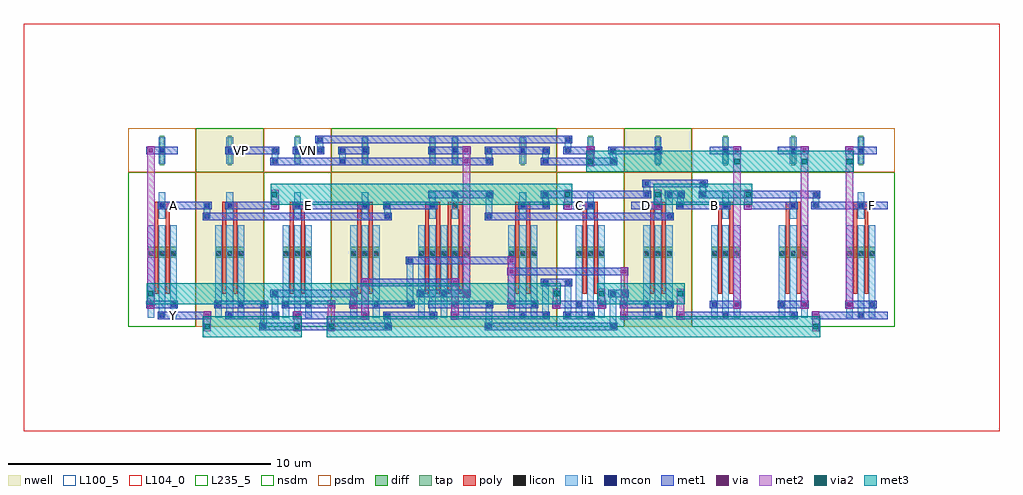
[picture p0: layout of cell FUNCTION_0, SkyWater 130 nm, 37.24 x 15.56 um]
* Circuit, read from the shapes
.subckt FUNCTION_0 A B C D E F VN VP Y
XM1 Y A VN VN sky130_fd_pr__nfet_01v8 w=0.42 l=0.15 m=2
XM2 Y E n1 VN sky130_fd_pr__nfet_01v8 w=0.42 l=0.15 m=2
XM3 Y C VN VN sky130_fd_pr__nfet_01v8 w=0.42 l=0.15 m=2
XM4 VN B VN VN sky130_fd_pr__nfet_01v8 w=0.42 l=0.15 m=2
XM5 VN D VN VN sky130_fd_pr__nfet_01v8 w=0.42 l=0.15 m=2
XM6 n1 F VN VN sky130_fd_pr__nfet_01v8 w=0.42 l=0.15 m=2
XM7 n2 C n3 VP sky130_fd_pr__pfet_01v8 w=0.42 l=0.15 m=2
XM8 Y E n2 VP sky130_fd_pr__pfet_01v8 w=0.42 l=0.15 m=2
XM9 n3 A VP VP sky130_fd_pr__pfet_01v8 w=0.42 l=0.15 m=2
XM10 n4 B VP VP sky130_fd_pr__pfet_01v8 w=0.42 l=0.15 m=2
XM11 Y F n2 VP sky130_fd_pr__pfet_01v8 w=0.42 l=0.15 m=2
XM12 n2 D n4 VP sky130_fd_pr__pfet_01v8 w=0.42 l=0.15 m=2
.ends

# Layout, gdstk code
from math import pi, radians
import gdstk
lib = gdstk.Library(unit=1e-6, precision=1e-09)
def R(c, l, rs):  # rectangles x0, y0, x1, y1
    for r in rs: c.add(gdstk.rectangle(r[:2], r[2:], *l))
def A(c, l, x, y, w, h, nx, ny, dx, dy):  # array of equal rectangles
    R(c, l, [(x+i*dx, y+j*dy, x+i*dx+w, y+j*dy+h) for i in range(nx) for j in range(ny)])
def P(c, l, *ps):  # polygons
    for p in ps: c.add(gdstk.Polygon(p, *l))
nwell = (64, 20)
diff = (65, 20)
tap = (65, 44)
poly = (66, 20)
licon = (66, 44)
li1 = (67, 20)
mcon = (67, 44)
met1 = (68, 20)
via = (68, 44)
met2 = (69, 20)
via2 = (69, 44)
met3 = (70, 20)
nsdm = (93, 44)
psdm = (94, 20)
L100_5 = (100, 5)
L104_0 = (104, 0)
L235_5 = (235, 5)

dp_pmos_89584417_x1_y1_1 = lib.new_cell('DP_PMOS_89584417_X1_Y1_1676811973')
R(dp_pmos_89584417_x1_y1_1, nwell, [(0,0,3.44,7.56)])
R(dp_pmos_89584417_x1_y1_1, diff, [(0.735,2.625,2.705,3.045)])
R(dp_pmos_89584417_x1_y1_1, tap, [(1.205,6.16,1.375,7.28), (2.065,6.16,2.235,7.28)])
A(dp_pmos_89584417_x1_y1_1, poly, 1, 1.26, 0.15, 3.36, 4, 1, 0.43, 0)
R(dp_pmos_89584417_x1_y1_1, poly, [(1,4.485,1.58,4.755), (1.86,4.485,2.44,4.755)])
A(dp_pmos_89584417_x1_y1_1, licon, 0.775, 2.705, 0.17, 0.17, 3, 1, 0.43, 0)
A(dp_pmos_89584417_x1_y1_1, licon, 1.635, 2.705, 0.17, 0.17, 3, 1, 0.43, 0)
R(dp_pmos_89584417_x1_y1_1, licon, [(1.205,4.535,1.375,4.705), (2.065,4.535,2.235,4.705), (1.205,6.635,1.375,6.805), (2.065,6.635,2.235,6.805)])
A(dp_pmos_89584417_x1_y1_1, li1, 0.735, 0.335, 0.25, 3.53, 5, 1, 0.43, 0)
R(dp_pmos_89584417_x1_y1_1, li1, [(1.165,4.115,1.415,5.125), (2.025,4.115,2.275,5.125), (1.165,6.215,1.415,7.225), (2.025,6.215,2.275,7.225)])
A(dp_pmos_89584417_x1_y1_1, mcon, 0.775, 1.175, 0.17, 0.17, 3, 1, 0.86, 0)
R(dp_pmos_89584417_x1_y1_1, mcon, [(1.205,0.335,1.375,0.505), (2.065,0.755,2.235,0.925), (1.205,4.535,1.375,4.705), (2.065,4.955,2.235,5.125), (1.205,6.635,1.375,6.805), (2.065,6.635,2.235,6.805)])
R(dp_pmos_89584417_x1_y1_1, met1, [(0.26,0.28,1.46,0.56), (1.12,0.7,2.32,0.98), (0.69,1.12,2.75,1.4), (0.26,4.48,1.46,4.76), (1.12,4.9,2.32,5.18), (1.12,6.58,2.75,6.86)])
R(dp_pmos_89584417_x1_y1_1, via, [(2.505,1.185,2.655,1.335), (2.505,6.645,2.655,6.795)])
R(dp_pmos_89584417_x1_y1_1, met2, [(2.44,1.1,2.72,6.88)])
R(dp_pmos_89584417_x1_y1_1, nsdm, [(0,5.88,3.44,7.56)])
R(dp_pmos_89584417_x1_y1_1, psdm, [(0,0,3.44,5.88)])
R(dp_pmos_89584417_x1_y1_1, L100_5, [(0,0,3.44,7.56)])

nmos_s_91441724_x1_y1_16 = lib.new_cell('NMOS_S_91441724_X1_Y1_1676811975')
R(nmos_s_91441724_x1_y1_16, diff, [(0.735,2.625,1.845,3.045)])
R(nmos_s_91441724_x1_y1_16, tap, [(1.205,6.16,1.375,7.28)])
R(nmos_s_91441724_x1_y1_16, poly, [(1,1.26,1.15,4.62), (1.43,1.26,1.58,4.62), (1,4.485,1.58,4.755)])
A(nmos_s_91441724_x1_y1_16, licon, 0.775, 2.705, 0.17, 0.17, 3, 1, 0.43, 0)
R(nmos_s_91441724_x1_y1_16, licon, [(1.205,4.535,1.375,4.705), (1.205,6.635,1.375,6.805)])
A(nmos_s_91441724_x1_y1_16, li1, 0.735, 0.335, 0.25, 3.53, 3, 1, 0.43, 0)
R(nmos_s_91441724_x1_y1_16, li1, [(1.165,4.115,1.415,5.125), (1.165,6.215,1.415,7.225)])
R(nmos_s_91441724_x1_y1_16, mcon, [(1.205,0.335,1.375,0.505), (0.775,0.755,0.945,0.925), (1.635,0.755,1.805,0.925), (1.205,4.535,1.375,4.705), (1.205,6.635,1.375,6.805)])
R(nmos_s_91441724_x1_y1_16, met1, [(0.26,0.28,1.46,0.56), (0.69,0.7,1.89,0.98), (0.26,4.48,1.46,4.76), (0.69,6.58,1.89,6.86)])
R(nmos_s_91441724_x1_y1_16, via, [(1.645,0.765,1.795,0.915), (1.645,6.645,1.795,6.795)])
R(nmos_s_91441724_x1_y1_16, met2, [(1.58,0.68,1.86,6.88)])
R(nmos_s_91441724_x1_y1_16, nsdm, [(0,0,2.58,5.88)])
R(nmos_s_91441724_x1_y1_16, psdm, [(0,5.88,2.58,7.56)])
R(nmos_s_91441724_x1_y1_16, L100_5, [(0,0,2.58,7.56)])

nmos_4t_21196599_x1_y1_1 = lib.new_cell('NMOS_4T_21196599_X1_Y1_1676811974')
R(nmos_4t_21196599_x1_y1_1, diff, [(0.735,2.625,1.845,3.045)])
R(nmos_4t_21196599_x1_y1_1, tap, [(1.205,6.16,1.375,7.28)])
R(nmos_4t_21196599_x1_y1_1, poly, [(1,1.26,1.15,4.62), (1.43,1.26,1.58,4.62), (1,4.485,1.58,4.755)])
A(nmos_4t_21196599_x1_y1_1, licon, 0.775, 2.705, 0.17, 0.17, 3, 1, 0.43, 0)
R(nmos_4t_21196599_x1_y1_1, licon, [(1.205,4.535,1.375,4.705), (1.205,6.635,1.375,6.805)])
A(nmos_4t_21196599_x1_y1_1, li1, 0.735, 0.335, 0.25, 3.53, 3, 1, 0.43, 0)
R(nmos_4t_21196599_x1_y1_1, li1, [(1.165,4.115,1.415,5.125), (1.165,6.215,1.415,7.225)])
R(nmos_4t_21196599_x1_y1_1, mcon, [(1.205,0.335,1.375,0.505), (0.775,0.755,0.945,0.925), (1.635,0.755,1.805,0.925), (1.205,4.535,1.375,4.705), (1.205,6.635,1.375,6.805)])
R(nmos_4t_21196599_x1_y1_1, met1, [(0.26,0.28,1.46,0.56), (0.69,0.7,1.89,0.98), (0.26,4.48,1.46,4.76), (0.26,6.58,1.46,6.86)])
R(nmos_4t_21196599_x1_y1_1, nsdm, [(0,0,2.58,5.88)])
R(nmos_4t_21196599_x1_y1_1, psdm, [(0,5.88,2.58,7.56)])
R(nmos_4t_21196599_x1_y1_1, L100_5, [(0,0,2.58,7.56)])

pmos_4t_77116389_x1_y1_1 = lib.new_cell('PMOS_4T_77116389_X1_Y1_1676811976')
R(pmos_4t_77116389_x1_y1_1, nwell, [(0,0,2.58,7.56)])
R(pmos_4t_77116389_x1_y1_1, diff, [(0.735,2.625,1.845,3.045)])
R(pmos_4t_77116389_x1_y1_1, tap, [(1.205,6.16,1.375,7.28)])
R(pmos_4t_77116389_x1_y1_1, poly, [(1,1.26,1.15,4.62), (1.43,1.26,1.58,4.62), (1,4.485,1.58,4.755)])
A(pmos_4t_77116389_x1_y1_1, licon, 0.775, 2.705, 0.17, 0.17, 3, 1, 0.43, 0)
R(pmos_4t_77116389_x1_y1_1, licon, [(1.205,4.535,1.375,4.705), (1.205,6.635,1.375,6.805)])
A(pmos_4t_77116389_x1_y1_1, li1, 0.735, 0.335, 0.25, 3.53, 3, 1, 0.43, 0)
R(pmos_4t_77116389_x1_y1_1, li1, [(1.165,4.115,1.415,5.125), (1.165,6.215,1.415,7.225)])
R(pmos_4t_77116389_x1_y1_1, mcon, [(1.205,0.335,1.375,0.505), (0.775,0.755,0.945,0.925), (1.635,0.755,1.805,0.925), (1.205,4.535,1.375,4.705), (1.205,6.635,1.375,6.805)])
R(pmos_4t_77116389_x1_y1_1, met1, [(0.26,0.28,1.46,0.56), (0.69,0.7,1.89,0.98), (0.26,4.48,1.46,4.76), (0.26,6.58,1.46,6.86)])
R(pmos_4t_77116389_x1_y1_1, nsdm, [(0,5.88,2.58,7.56)])
R(pmos_4t_77116389_x1_y1_1, psdm, [(0,0,2.58,5.88)])
R(pmos_4t_77116389_x1_y1_1, L100_5, [(0,0,2.58,7.56)])

function_0 = lib.new_cell('FUNCTION_0')
A(function_0, li1, 15.785, 4.62, 0.25, 0.42, 3, 1, 5.16, 0)
R(function_0, li1, [(5.035,-0.085,5.285,0.085), (5.035,-0.085,5.285,0.085), (9.765,-0.085,10.015,0.085), (9.765,-0.085,10.015,0.085), (13.635,-0.085,13.885,0.085), (13.635,-0.085,13.885,0.085), (18.365,-0.085,18.615,0.085), (18.365,-0.085,18.615,0.085), (5.035,0,5.285,0.84), (9.765,0,10.015,0.42), (13.635,0,13.885,0.84), (18.365,0,18.615,1.26), (5.465,0.335,5.715,0.505), (5.465,0.335,5.715,0.505), (5.465,0.335,5.715,0.505), (5.465,0.335,5.715,0.505), (5.465,0.335,5.715,0.505), (5.465,0.335,5.715,0.505), (9.765,0.335,10.015,0.505), (9.765,0.335,10.015,0.505), (15.785,0.335,16.035,0.505), (15.785,0.335,16.035,0.505), (16.645,0.335,16.895,0.505), (16.645,0.335,16.895,0.505), (5.465,0.42,5.715,1.26), (15.785,0.42,16.035,1.68), (16.645,0.42,16.895,1.68), (5.035,0.755,5.285,0.925), (5.035,0.755,5.285,0.925), (10.625,0.755,10.875,0.925), (10.625,0.755,10.875,0.925), (10.625,0.755,10.875,0.925), (10.625,0.755,10.875,0.925), (13.635,0.755,13.885,0.925), (13.635,0.755,13.885,0.925), (18.795,0.755,19.045,0.925), (18.795,0.755,19.045,0.925), (10.625,0.84,10.875,2.52), (18.795,0.84,19.045,1.26), (5.465,1.175,5.715,1.345), (5.465,1.175,5.715,1.345), (5.465,1.175,5.715,1.345), (5.465,1.175,5.715,1.345), (5.465,1.175,5.715,1.345), (5.465,1.175,5.715,1.345), (18.365,1.175,18.615,1.345), (18.365,1.175,18.615,1.345), (18.795,1.175,19.045,1.345), (18.795,1.175,19.045,1.345), (15.785,1.595,16.035,1.765), (15.785,1.595,16.035,1.765), (16.645,1.595,16.895,1.765), (16.645,1.595,16.895,1.765), (10.625,2.435,10.875,2.605), (10.625,2.435,10.875,2.605), (10.625,2.435,10.875,2.605), (10.625,2.435,10.875,2.605), (2.885,4.115,3.135,4.285), (2.885,4.115,3.135,4.285), (9.765,4.115,10.015,4.285), (9.765,4.115,10.015,4.285), (13.635,4.115,13.885,4.285), (13.635,4.115,13.885,4.285), (20.515,4.115,20.765,4.285), (20.515,4.115,20.765,4.285), (2.885,4.2,3.135,4.62), (9.765,4.2,10.015,4.62), (13.635,4.2,13.885,5.04), (20.515,4.2,20.765,5.04), (2.885,4.535,3.135,4.705), (2.885,4.535,3.135,4.705), (9.765,4.535,10.015,4.705), (9.765,4.535,10.015,4.705), (15.785,4.535,16.035,4.705), (15.785,4.535,16.035,4.705), (20.945,4.535,21.195,4.705), (20.945,4.535,21.195,4.705), (26.105,4.535,26.355,4.705), (26.105,4.535,26.355,4.705), (13.635,4.955,13.885,5.125), (13.635,4.955,13.885,5.125), (15.785,4.955,16.035,5.125), (15.785,4.955,16.035,5.125), (19.655,4.955,19.905,5.125), (19.655,4.955,19.905,5.125), (20.515,4.955,20.765,5.125), (20.515,4.955,20.765,5.125), (20.945,4.955,21.195,5.125), (20.945,4.955,21.195,5.125), (21.805,4.955,22.055,5.125), (21.805,4.955,22.055,5.125), (26.105,4.955,26.355,5.125), (26.105,4.955,26.355,5.125), (19.655,5.04,19.905,5.46), (21.805,5.04,22.055,5.46), (19.655,5.375,19.905,5.545), (19.655,5.375,19.905,5.545), (21.805,5.375,22.055,5.545), (21.805,5.375,22.055,5.545), (5.465,6.215,5.715,6.385), (5.465,6.215,5.715,6.385), (5.465,6.215,5.715,6.385), (5.465,6.215,5.715,6.385), (5.465,6.215,5.715,6.385), (5.465,6.215,5.715,6.385), (5.465,6.215,5.715,6.385), (5.465,6.215,5.715,6.385), (8.045,6.215,8.295,6.385), (8.045,6.215,8.295,6.385), (8.045,6.215,8.295,6.385), (8.045,6.215,8.295,6.385), (8.045,6.215,8.295,6.385), (8.045,6.215,8.295,6.385), (8.045,6.215,8.295,6.385), (8.045,6.215,8.295,6.385), (13.635,6.215,13.885,6.385), (13.635,6.215,13.885,6.385), (13.635,6.215,13.885,6.385), (13.635,6.215,13.885,6.385), (13.635,6.215,13.885,6.385), (13.635,6.215,13.885,6.385), (15.785,6.215,16.035,6.385), (15.785,6.215,16.035,6.385), (15.785,6.215,16.035,6.385), (15.785,6.215,16.035,6.385), (18.365,6.215,18.615,6.385), (18.365,6.215,18.615,6.385), (18.365,6.215,18.615,6.385), (18.365,6.215,18.615,6.385), (5.465,6.3,5.715,6.72), (8.045,6.3,8.295,6.72), (13.635,6.3,13.885,6.72), (15.785,6.3,16.035,6.72), (18.365,6.3,18.615,6.72), (5.465,6.635,5.715,6.805), (5.465,6.635,5.715,6.805), (5.465,6.635,5.715,6.805), (5.465,6.635,5.715,6.805), (5.465,6.635,5.715,6.805), (5.465,6.635,5.715,6.805), (5.465,6.635,5.715,6.805), (5.465,6.635,5.715,6.805), (7.185,6.635,7.435,6.805), (7.185,6.635,7.435,6.805), (7.185,6.635,7.435,6.805), (7.185,6.635,7.435,6.805), (7.185,6.635,7.435,6.805), (7.185,6.635,7.435,6.805), (7.185,6.635,7.435,6.805), (7.185,6.635,7.435,6.805), (8.045,6.635,8.295,6.805), (8.045,6.635,8.295,6.805), (8.045,6.635,8.295,6.805), (8.045,6.635,8.295,6.805), (8.045,6.635,8.295,6.805), (8.045,6.635,8.295,6.805), (8.045,6.635,8.295,6.805), (8.045,6.635,8.295,6.805), (13.635,6.635,13.885,6.805), (13.635,6.635,13.885,6.805), (13.635,6.635,13.885,6.805), (13.635,6.635,13.885,6.805), (13.635,6.635,13.885,6.805), (13.635,6.635,13.885,6.805), (15.785,6.635,16.035,6.805), (15.785,6.635,16.035,6.805), (15.785,6.635,16.035,6.805), (15.785,6.635,16.035,6.805), (16.645,6.635,16.895,6.805), (16.645,6.635,16.895,6.805), (16.645,6.635,16.895,6.805), (16.645,6.635,16.895,6.805), (16.645,6.635,16.895,6.805), (16.645,6.635,16.895,6.805), (16.645,6.635,16.895,6.805), (16.645,6.635,16.895,6.805), (18.365,6.635,18.615,6.805), (18.365,6.635,18.615,6.805), (18.365,6.635,18.615,6.805), (18.365,6.635,18.615,6.805), (7.185,6.72,7.435,7.14), (16.645,6.72,16.895,7.14), (7.185,7.055,7.435,7.225), (7.185,7.055,7.435,7.225), (7.185,7.055,7.435,7.225), (7.185,7.055,7.435,7.225), (7.185,7.055,7.435,7.225), (7.185,7.055,7.435,7.225), (7.185,7.055,7.435,7.225), (7.185,7.055,7.435,7.225), (16.645,7.055,16.895,7.225), (16.645,7.055,16.895,7.225), (16.645,7.055,16.895,7.225), (16.645,7.055,16.895,7.225), (16.645,7.055,16.895,7.225), (16.645,7.055,16.895,7.225), (16.645,7.055,16.895,7.225), (16.645,7.055,16.895,7.225)])
R(function_0, mcon, [(5.075,-0.085,5.245,0.085), (5.075,-0.085,5.245,0.085), (9.805,-0.085,9.975,0.085), (9.805,-0.085,9.975,0.085), (13.675,-0.085,13.845,0.085), (13.675,-0.085,13.845,0.085), (18.405,-0.085,18.575,0.085), (18.405,-0.085,18.575,0.085), (5.505,0.335,5.675,0.505), (5.505,0.335,5.675,0.505), (5.505,0.335,5.675,0.505), (5.505,0.335,5.675,0.505), (5.505,0.335,5.675,0.505), (5.505,0.335,5.675,0.505), (9.805,0.335,9.975,0.505), (9.805,0.335,9.975,0.505), (15.825,0.335,15.995,0.505), (15.825,0.335,15.995,0.505), (16.685,0.335,16.855,0.505), (16.685,0.335,16.855,0.505), (5.075,0.755,5.245,0.925), (5.075,0.755,5.245,0.925), (10.665,0.755,10.835,0.925), (10.665,0.755,10.835,0.925), (10.665,0.755,10.835,0.925), (10.665,0.755,10.835,0.925), (13.675,0.755,13.845,0.925), (13.675,0.755,13.845,0.925), (18.835,0.755,19.005,0.925), (18.835,0.755,19.005,0.925), (5.505,1.175,5.675,1.345), (5.505,1.175,5.675,1.345), (5.505,1.175,5.675,1.345), (5.505,1.175,5.675,1.345), (5.505,1.175,5.675,1.345), (5.505,1.175,5.675,1.345), (18.405,1.175,18.575,1.345), (18.405,1.175,18.575,1.345), (18.835,1.175,19.005,1.345), (18.835,1.175,19.005,1.345), (15.825,1.595,15.995,1.765), (15.825,1.595,15.995,1.765), (16.685,1.595,16.855,1.765), (16.685,1.595,16.855,1.765), (10.665,2.435,10.835,2.605), (10.665,2.435,10.835,2.605), (10.665,2.435,10.835,2.605), (10.665,2.435,10.835,2.605), (2.925,4.115,3.095,4.285), (2.925,4.115,3.095,4.285), (9.805,4.115,9.975,4.285), (9.805,4.115,9.975,4.285), (13.675,4.115,13.845,4.285), (13.675,4.115,13.845,4.285), (20.555,4.115,20.725,4.285), (20.555,4.115,20.725,4.285), (2.925,4.535,3.095,4.705), (2.925,4.535,3.095,4.705), (9.805,4.535,9.975,4.705), (9.805,4.535,9.975,4.705), (15.825,4.535,15.995,4.705), (15.825,4.535,15.995,4.705), (20.985,4.535,21.155,4.705), (20.985,4.535,21.155,4.705), (26.145,4.535,26.315,4.705), (26.145,4.535,26.315,4.705), (13.675,4.955,13.845,5.125), (13.675,4.955,13.845,5.125), (15.825,4.955,15.995,5.125), (15.825,4.955,15.995,5.125), (19.695,4.955,19.865,5.125), (19.695,4.955,19.865,5.125), (20.555,4.955,20.725,5.125), (20.555,4.955,20.725,5.125), (20.985,4.955,21.155,5.125), (20.985,4.955,21.155,5.125), (21.845,4.955,22.015,5.125), (21.845,4.955,22.015,5.125), (26.145,4.955,26.315,5.125), (26.145,4.955,26.315,5.125), (19.695,5.375,19.865,5.545), (19.695,5.375,19.865,5.545), (21.845,5.375,22.015,5.545), (21.845,5.375,22.015,5.545), (5.505,6.215,5.675,6.385), (5.505,6.215,5.675,6.385), (5.505,6.215,5.675,6.385), (5.505,6.215,5.675,6.385), (5.505,6.215,5.675,6.385), (5.505,6.215,5.675,6.385), (5.505,6.215,5.675,6.385), (5.505,6.215,5.675,6.385), (8.085,6.215,8.255,6.385), (8.085,6.215,8.255,6.385), (8.085,6.215,8.255,6.385), (8.085,6.215,8.255,6.385), (8.085,6.215,8.255,6.385), (8.085,6.215,8.255,6.385), (8.085,6.215,8.255,6.385), (8.085,6.215,8.255,6.385), (13.675,6.215,13.845,6.385), (13.675,6.215,13.845,6.385), (13.675,6.215,13.845,6.385), (13.675,6.215,13.845,6.385), (13.675,6.215,13.845,6.385), (13.675,6.215,13.845,6.385), (15.825,6.215,15.995,6.385), (15.825,6.215,15.995,6.385), (15.825,6.215,15.995,6.385), (15.825,6.215,15.995,6.385), (18.405,6.215,18.575,6.385), (18.405,6.215,18.575,6.385), (18.405,6.215,18.575,6.385), (18.405,6.215,18.575,6.385), (5.505,6.635,5.675,6.805), (5.505,6.635,5.675,6.805), (5.505,6.635,5.675,6.805), (5.505,6.635,5.675,6.805), (5.505,6.635,5.675,6.805), (5.505,6.635,5.675,6.805), (5.505,6.635,5.675,6.805), (5.505,6.635,5.675,6.805), (7.225,6.635,7.395,6.805), (7.225,6.635,7.395,6.805), (7.225,6.635,7.395,6.805), (7.225,6.635,7.395,6.805), (7.225,6.635,7.395,6.805), (7.225,6.635,7.395,6.805), (7.225,6.635,7.395,6.805), (7.225,6.635,7.395,6.805), (8.085,6.635,8.255,6.805), (8.085,6.635,8.255,6.805), (8.085,6.635,8.255,6.805), (8.085,6.635,8.255,6.805), (8.085,6.635,8.255,6.805), (8.085,6.635,8.255,6.805), (8.085,6.635,8.255,6.805), (8.085,6.635,8.255,6.805), (13.675,6.635,13.845,6.805), (13.675,6.635,13.845,6.805), (13.675,6.635,13.845,6.805), (13.675,6.635,13.845,6.805), (13.675,6.635,13.845,6.805), (13.675,6.635,13.845,6.805), (15.825,6.635,15.995,6.805), (15.825,6.635,15.995,6.805), (15.825,6.635,15.995,6.805), (15.825,6.635,15.995,6.805), (16.685,6.635,16.855,6.805), (16.685,6.635,16.855,6.805), (16.685,6.635,16.855,6.805), (16.685,6.635,16.855,6.805), (16.685,6.635,16.855,6.805), (16.685,6.635,16.855,6.805), (16.685,6.635,16.855,6.805), (16.685,6.635,16.855,6.805), (18.405,6.635,18.575,6.805), (18.405,6.635,18.575,6.805), (18.405,6.635,18.575,6.805), (18.405,6.635,18.575,6.805), (7.225,7.055,7.395,7.225), (7.225,7.055,7.395,7.225), (7.225,7.055,7.395,7.225), (7.225,7.055,7.395,7.225), (7.225,7.055,7.395,7.225), (7.225,7.055,7.395,7.225), (7.225,7.055,7.395,7.225), (7.225,7.055,7.395,7.225), (16.685,7.055,16.855,7.225), (16.685,7.055,16.855,7.225), (16.685,7.055,16.855,7.225), (16.685,7.055,16.855,7.225), (16.685,7.055,16.855,7.225), (16.685,7.055,16.855,7.225), (16.685,7.055,16.855,7.225), (16.685,7.055,16.855,7.225)])
A(function_0, met1, 2.15, 0.28, 0.86, 0.28, 4, 2, 2.58, 4.2)
R(function_0, met1, [(4.99,-0.14,5.33,0.14), (4.99,-0.14,5.33,0.14), (5.16,-0.14,9.89,0.14), (9.72,-0.14,10.06,0.14), (9.72,-0.14,10.06,0.14), (13.59,-0.14,13.93,0.14), (13.59,-0.14,13.93,0.14), (13.76,-0.14,18.49,0.14), (18.32,-0.14,18.66,0.14), (18.32,-0.14,18.66,0.14), (2.85,0.28,3.17,0.56), (2.85,0.28,3.17,0.56), (2.85,0.28,3.17,0.56), (2.85,0.28,3.17,0.56), (2.85,0.28,3.17,0.56), (2.85,0.28,3.17,0.56), (2.85,0.28,3.17,0.56), (2.85,0.28,3.17,0.56), (5.42,0.28,5.76,0.56), (5.42,0.28,5.76,0.56), (5.42,0.28,5.76,0.56), (5.42,0.28,5.76,0.56), (5.42,0.28,5.76,0.56), (5.42,0.28,5.76,0.56), (6.29,0.28,6.61,0.56), (6.29,0.28,6.61,0.56), (6.29,0.28,6.61,0.56), (6.29,0.28,6.61,0.56), (6.29,0.28,6.61,0.56), (6.29,0.28,6.61,0.56), (6.29,0.28,6.61,0.56), (6.29,0.28,6.61,0.56), (8.87,0.28,9.19,0.56), (8.87,0.28,9.19,0.56), (8.87,0.28,9.19,0.56), (8.87,0.28,9.19,0.56), (9.72,0.28,10.06,0.56), (9.72,0.28,10.06,0.56), (12.31,0.28,12.63,0.56), (12.31,0.28,12.63,0.56), (12.31,0.28,12.63,0.56), (12.31,0.28,12.63,0.56), (12.47,0.28,15.05,0.56), (15.74,0.28,16.08,0.56), (15.74,0.28,16.08,0.56), (16.6,0.28,16.94,0.56), (16.6,0.28,16.94,0.56), (18.76,0.28,19.08,0.56), (18.76,0.28,19.08,0.56), (18.92,0.28,19.35,0.56), (20.91,0.28,21.23,0.56), (20.91,0.28,21.23,0.56), (20.91,0.28,21.23,0.56), (20.91,0.28,21.23,0.56), (21.07,0.28,21.93,0.56), (22.79,0.28,24.51,0.56), (26.07,0.28,26.39,0.56), (26.07,0.28,26.39,0.56), (26.23,0.28,27.95,0.56), (4.3,0.7,5.16,0.98), (4.99,0.7,5.33,0.98), (4.99,0.7,5.33,0.98), (6.88,0.7,7.74,0.98), (7.58,0.7,7.9,0.98), (7.58,0.7,7.9,0.98), (8.44,0.7,8.76,0.98), (8.44,0.7,8.76,0.98), (8.44,0.7,8.76,0.98), (8.44,0.7,8.76,0.98), (8.44,0.7,8.76,0.98), (8.44,0.7,8.76,0.98), (9.46,0.7,10.75,0.98), (10.58,0.7,10.92,0.98), (10.58,0.7,10.92,0.98), (10.58,0.7,10.92,0.98), (10.58,0.7,10.92,0.98), (12.47,0.7,13.76,0.98), (13.59,0.7,13.93,0.98), (13.59,0.7,13.93,0.98), (14.46,0.7,14.78,0.98), (14.46,0.7,14.78,0.98), (14.46,0.7,14.78,0.98), (14.46,0.7,14.78,0.98), (16.18,0.7,16.5,0.98), (16.18,0.7,16.5,0.98), (16.18,0.7,16.5,0.98), (16.18,0.7,16.5,0.98), (16.18,0.7,16.5,0.98), (16.18,0.7,16.5,0.98), (16.34,0.7,17.2,0.98), (17.9,0.7,18.22,0.98), (17.9,0.7,18.22,0.98), (17.9,0.7,18.22,0.98), (17.9,0.7,18.22,0.98), (18.75,0.7,19.09,0.98), (18.75,0.7,19.09,0.98), (18.92,0.7,19.78,0.98), (5.42,1.12,5.76,1.4), (5.42,1.12,5.76,1.4), (5.42,1.12,5.76,1.4), (5.42,1.12,5.76,1.4), (5.42,1.12,5.76,1.4), (5.42,1.12,5.76,1.4), (5.59,1.12,8.6,1.4), (8.44,1.12,8.76,1.4), (8.44,1.12,8.76,1.4), (8.44,1.12,8.76,1.4), (8.44,1.12,8.76,1.4), (8.44,1.12,8.76,1.4), (8.44,1.12,8.76,1.4), (18.32,1.12,18.66,1.4), (18.32,1.12,18.66,1.4), (18.49,1.12,18.92,1.4), (18.75,1.12,19.09,1.4), (18.75,1.12,19.09,1.4), (8.87,1.54,9.19,1.82), (8.87,1.54,9.19,1.82), (8.87,1.54,9.19,1.82), (8.87,1.54,9.19,1.82), (9.03,1.54,12.47,1.82), (12.31,1.54,12.63,1.82), (12.31,1.54,12.63,1.82), (12.31,1.54,12.63,1.82), (12.31,1.54,12.63,1.82), (15.74,1.54,16.08,1.82), (15.74,1.54,16.08,1.82), (15.91,1.54,16.77,1.82), (16.6,1.54,16.94,1.82), (16.6,1.54,16.94,1.82), (14.46,1.96,14.78,2.24), (14.46,1.96,14.78,2.24), (14.62,1.96,18.92,2.24), (18.76,1.96,19.08,2.24), (18.76,1.96,19.08,2.24), (10.58,2.38,10.92,2.66), (10.58,2.38,10.92,2.66), (10.58,2.38,10.92,2.66), (10.58,2.38,10.92,2.66), (10.75,2.38,14.62,2.66), (14.46,2.38,14.78,2.66), (14.46,2.38,14.78,2.66), (14.46,2.38,14.78,2.66), (14.46,2.38,14.78,2.66), (2.84,4.06,3.18,4.34), (2.84,4.06,3.18,4.34), (3.01,4.06,9.89,4.34), (9.72,4.06,10.06,4.34), (9.72,4.06,10.06,4.34), (13.59,4.06,13.93,4.34), (13.59,4.06,13.93,4.34), (13.76,4.06,20.64,4.34), (20.47,4.06,20.81,4.34), (20.47,4.06,20.81,4.34), (2.84,4.48,3.18,4.76), (2.84,4.48,3.18,4.76), (5.43,4.48,5.75,4.76), (5.43,4.48,5.75,4.76), (9.72,4.48,10.06,4.76), (9.72,4.48,10.06,4.76), (15.74,4.48,16.08,4.76), (15.74,4.48,16.08,4.76), (16.61,4.48,16.93,4.76), (16.61,4.48,16.93,4.76), (20.05,4.48,20.37,4.76), (20.05,4.48,20.37,4.76), (20.9,4.48,21.24,4.76), (20.9,4.48,21.24,4.76), (21.07,4.48,21.93,4.76), (23.49,4.48,23.81,4.76), (23.49,4.48,23.81,4.76), (23.65,4.48,24.51,4.76), (26.06,4.48,26.4,4.76), (26.06,4.48,26.4,4.76), (26.23,4.48,27.95,4.76), (12.47,4.9,13.76,5.18), (13.59,4.9,13.93,5.18), (13.59,4.9,13.93,5.18), (15.74,4.9,16.08,5.18), (15.74,4.9,16.08,5.18), (15.91,4.9,19.78,5.18), (19.61,4.9,19.95,5.18), (19.61,4.9,19.95,5.18), (20.47,4.9,20.81,5.18), (20.47,4.9,20.81,5.18), (20.64,4.9,21.07,5.18), (20.9,4.9,21.24,5.18), (20.9,4.9,21.24,5.18), (21.76,4.9,22.1,5.18), (21.76,4.9,22.1,5.18), (21.93,4.9,26.23,5.18), (26.06,4.9,26.4,5.18), (26.06,4.9,26.4,5.18), (19.61,5.32,19.95,5.6), (19.61,5.32,19.95,5.6), (19.78,5.32,21.93,5.6), (21.76,5.32,22.1,5.6), (21.76,5.32,22.1,5.6), (5.42,6.16,5.76,6.44), (5.42,6.16,5.76,6.44), (5.42,6.16,5.76,6.44), (5.42,6.16,5.76,6.44), (5.42,6.16,5.76,6.44), (5.42,6.16,5.76,6.44), (5.42,6.16,5.76,6.44), (5.42,6.16,5.76,6.44), (5.59,6.16,8.17,6.44), (8,6.16,8.34,6.44), (8,6.16,8.34,6.44), (8,6.16,8.34,6.44), (8,6.16,8.34,6.44), (8,6.16,8.34,6.44), (8,6.16,8.34,6.44), (8,6.16,8.34,6.44), (8,6.16,8.34,6.44), (8.17,6.16,13.76,6.44), (12.74,6.16,13.06,6.44), (12.74,6.16,13.06,6.44), (13.59,6.16,13.93,6.44), (13.59,6.16,13.93,6.44), (13.59,6.16,13.93,6.44), (13.59,6.16,13.93,6.44), (13.59,6.16,13.93,6.44), (13.59,6.16,13.93,6.44), (15.74,6.16,16.08,6.44), (15.74,6.16,16.08,6.44), (15.74,6.16,16.08,6.44), (15.74,6.16,16.08,6.44), (15.91,6.16,18.49,6.44), (18.32,6.16,18.66,6.44), (18.32,6.16,18.66,6.44), (18.32,6.16,18.66,6.44), (18.32,6.16,18.66,6.44), (4.73,6.58,5.59,6.86), (5.42,6.58,5.76,6.86), (5.42,6.58,5.76,6.86), (5.42,6.58,5.76,6.86), (5.42,6.58,5.76,6.86), (5.42,6.58,5.76,6.86), (5.42,6.58,5.76,6.86), (5.42,6.58,5.76,6.86), (5.42,6.58,5.76,6.86), (7.14,6.58,7.48,6.86), (7.14,6.58,7.48,6.86), (7.14,6.58,7.48,6.86), (7.14,6.58,7.48,6.86), (7.14,6.58,7.48,6.86), (7.14,6.58,7.48,6.86), (7.14,6.58,7.48,6.86), (7.14,6.58,7.48,6.86), (8,6.58,8.34,6.86), (8,6.58,8.34,6.86), (8,6.58,8.34,6.86), (8,6.58,8.34,6.86), (8,6.58,8.34,6.86), (8,6.58,8.34,6.86), (8,6.58,8.34,6.86), (8,6.58,8.34,6.86), (13.59,6.58,13.93,6.86), (13.59,6.58,13.93,6.86), (13.59,6.58,13.93,6.86), (13.59,6.58,13.93,6.86), (13.59,6.58,13.93,6.86), (13.59,6.58,13.93,6.86), (13.76,6.58,15.05,6.86), (15.74,6.58,16.08,6.86), (15.74,6.58,16.08,6.86), (15.74,6.58,16.08,6.86), (15.74,6.58,16.08,6.86), (16.6,6.58,16.94,6.86), (16.6,6.58,16.94,6.86), (16.6,6.58,16.94,6.86), (16.6,6.58,16.94,6.86), (16.6,6.58,16.94,6.86), (16.6,6.58,16.94,6.86), (16.6,6.58,16.94,6.86), (16.6,6.58,16.94,6.86), (17.47,6.58,17.79,6.86), (17.47,6.58,17.79,6.86), (17.47,6.58,17.79,6.86), (17.47,6.58,17.79,6.86), (17.47,6.58,17.79,6.86), (17.47,6.58,17.79,6.86), (18.32,6.58,18.66,6.86), (18.32,6.58,18.66,6.86), (18.32,6.58,18.66,6.86), (18.32,6.58,18.66,6.86), (18.49,6.58,19.35,6.86), (7.14,7,7.48,7.28), (7.14,7,7.48,7.28), (7.14,7,7.48,7.28), (7.14,7,7.48,7.28), (7.14,7,7.48,7.28), (7.14,7,7.48,7.28), (7.14,7,7.48,7.28), (7.14,7,7.48,7.28), (7.31,7,16.77,7.28), (16.6,7,16.94,7.28), (16.6,7,16.94,7.28), (16.6,7,16.94,7.28), (16.6,7,16.94,7.28), (16.6,7,16.94,7.28), (16.6,7,16.94,7.28), (16.6,7,16.94,7.28), (16.6,7,16.94,7.28)])
P(function_0, met1, [(0,0),(0,0),(0,0),(0,0)],
  [(0,0),(0,0),(0,0),(0,0)],
  [(0,0),(0,0),(0,0),(0,0)],
  [(0,0),(0,0),(0,0),(0,0)],
  [(0,0),(0,0),(0,0),(0,0)],
  [(0,0),(0,0),(0,0),(0,0)],
  [(0,0),(0,0),(0,0),(0,0)],
  [(0,0),(0,0),(0,0),(0,0)],
  [(0,0),(0,0),(0,0),(0,0)],
  [(0,0),(0,0),(0,0),(0,0)],
  [(0,0),(0,0),(0,0),(0,0)],
  [(0,0),(0,0),(0,0),(0,0)],
  [(0,0),(0,0),(0,0),(0,0)],
  [(0,0),(0,0),(0,0),(0,0)],
  [(0,0),(0,0),(0,0),(0,0)],
  [(0,0),(0,0),(0,0),(0,0)],
  [(0,0),(0,0),(0,0),(0,0)],
  [(0,0),(0,0),(0,0),(0,0)],
  [(0,0),(0,0),(0,0),(0,0)],
  [(0,0),(0,0),(0,0),(0,0)],
  [(0,0),(0,0),(0,0),(0,0)],
  [(0,0),(0,0),(0,0),(0,0)],
  [(0,0),(0,0),(0,0),(0,0)],
  [(0,0),(0,0),(0,0),(0,0)],
  [(0,0),(0,0),(0,0),(0,0)],
  [(0,0),(0,0),(0,0),(0,0)],
  [(0,0),(0,0),(0,0),(0,0)],
  [(0,0),(0,0),(0,0),(0,0)],
  [(0,0),(0,0),(0,0),(0,0)],
  [(0,0),(0,0),(0,0),(0,0)],
  [(0,0),(0,0),(0,0),(0,0)],
  [(0,0),(0,0),(0,0),(0,0)],
  [(0,0),(0,0),(0,0),(0,0)],
  [(0,0),(0,0),(0,0),(0,0)],
  [(0,0),(0,0),(0,0),(0,0)],
  [(0,0),(0,0),(0,0),(0,0)],
  [(0,0),(0,0),(0,0),(0,0)],
  [(0,0),(0,0),(0,0),(0,0)],
  [(0,0),(0,0),(0,0),(0,0)],
  [(0,0),(0,0),(0,0),(0,0)],
  [(0,0),(0,0),(0,0),(0,0)],
  [(0,0),(0,0),(0,0),(0,0)],
  [(0,0),(0,0),(0,0),(0,0)],
  [(0,0),(0,0),(0,0),(0,0)],
  [(0,0),(0,0),(0,0),(0,0)])
R(function_0, via, [(2.935,0.345,3.085,0.495), (2.935,0.345,3.085,0.495), (2.935,0.345,3.085,0.495), (2.935,0.345,3.085,0.495), (2.935,0.345,3.085,0.495), (2.935,0.345,3.085,0.495), (2.935,0.345,3.085,0.495), (2.935,0.345,3.085,0.495), (6.375,0.345,6.525,0.495), (6.375,0.345,6.525,0.495), (6.375,0.345,6.525,0.495), (6.375,0.345,6.525,0.495), (6.375,0.345,6.525,0.495), (6.375,0.345,6.525,0.495), (6.375,0.345,6.525,0.495), (6.375,0.345,6.525,0.495), (8.955,0.345,9.105,0.495), (8.955,0.345,9.105,0.495), (8.955,0.345,9.105,0.495), (8.955,0.345,9.105,0.495), (12.395,0.345,12.545,0.495), (12.395,0.345,12.545,0.495), (12.395,0.345,12.545,0.495), (12.395,0.345,12.545,0.495), (18.845,0.345,18.995,0.495), (18.845,0.345,18.995,0.495), (20.995,0.345,21.145,0.495), (20.995,0.345,21.145,0.495), (20.995,0.345,21.145,0.495), (20.995,0.345,21.145,0.495), (26.155,0.345,26.305,0.495), (26.155,0.345,26.305,0.495), (7.665,0.765,7.815,0.915), (7.665,0.765,7.815,0.915), (8.525,0.765,8.675,0.915), (8.525,0.765,8.675,0.915), (8.525,0.765,8.675,0.915), (8.525,0.765,8.675,0.915), (8.525,0.765,8.675,0.915), (8.525,0.765,8.675,0.915), (14.545,0.765,14.695,0.915), (14.545,0.765,14.695,0.915), (14.545,0.765,14.695,0.915), (14.545,0.765,14.695,0.915), (16.265,0.765,16.415,0.915), (16.265,0.765,16.415,0.915), (16.265,0.765,16.415,0.915), (16.265,0.765,16.415,0.915), (16.265,0.765,16.415,0.915), (16.265,0.765,16.415,0.915), (17.985,0.765,18.135,0.915), (17.985,0.765,18.135,0.915), (17.985,0.765,18.135,0.915), (17.985,0.765,18.135,0.915), (8.525,1.185,8.675,1.335), (8.525,1.185,8.675,1.335), (8.525,1.185,8.675,1.335), (8.525,1.185,8.675,1.335), (8.525,1.185,8.675,1.335), (8.525,1.185,8.675,1.335), (8.955,1.605,9.105,1.755), (8.955,1.605,9.105,1.755), (8.955,1.605,9.105,1.755), (8.955,1.605,9.105,1.755), (12.395,1.605,12.545,1.755), (12.395,1.605,12.545,1.755), (12.395,1.605,12.545,1.755), (12.395,1.605,12.545,1.755), (14.545,2.025,14.695,2.175), (14.545,2.025,14.695,2.175), (18.845,2.025,18.995,2.175), (18.845,2.025,18.995,2.175), (14.545,2.445,14.695,2.595), (14.545,2.445,14.695,2.595), (14.545,2.445,14.695,2.595), (14.545,2.445,14.695,2.595), (5.515,4.545,5.665,4.695), (5.515,4.545,5.665,4.695), (16.695,4.545,16.845,4.695), (16.695,4.545,16.845,4.695), (20.135,4.545,20.285,4.695), (20.135,4.545,20.285,4.695), (23.575,4.545,23.725,4.695), (23.575,4.545,23.725,4.695), (12.825,6.225,12.975,6.375), (12.825,6.225,12.975,6.375), (17.555,6.645,17.705,6.795), (17.555,6.645,17.705,6.795), (17.555,6.645,17.705,6.795), (17.555,6.645,17.705,6.795), (17.555,6.645,17.705,6.795), (17.555,6.645,17.705,6.795)])
A(function_0, met2, 16.63, 4.62, 0.28, 0.42, 3, 1, 3.44, 0)
R(function_0, met2, [(2.87,-0.185,3.15,0.185), (2.87,-0.185,3.15,0.185), (2.87,-0.185,3.15,0.185), (2.87,-0.185,3.15,0.185), (2.87,-0.185,3.15,0.185), (2.87,-0.185,3.15,0.185), (2.87,-0.185,3.15,0.185), (2.87,-0.185,3.15,0.185), (6.31,-0.185,6.59,0.185), (6.31,-0.185,6.59,0.185), (6.31,-0.185,6.59,0.185), (6.31,-0.185,6.59,0.185), (6.31,-0.185,6.59,0.185), (6.31,-0.185,6.59,0.185), (6.31,-0.185,6.59,0.185), (6.31,-0.185,6.59,0.185), (7.6,-0.185,7.88,0.185), (7.6,-0.185,7.88,0.185), (26.09,-0.185,26.37,0.185), (26.09,-0.185,26.37,0.185), (2.87,0,3.15,0.42), (6.31,0,6.59,0.42), (7.6,0,7.88,0.84), (26.09,0,26.37,0.42), (2.87,0.26,3.15,0.58), (2.87,0.26,3.15,0.58), (2.87,0.26,3.15,0.58), (2.87,0.26,3.15,0.58), (2.87,0.26,3.15,0.58), (2.87,0.26,3.15,0.58), (2.87,0.26,3.15,0.58), (2.87,0.26,3.15,0.58), (6.31,0.26,6.59,0.58), (6.31,0.26,6.59,0.58), (6.31,0.26,6.59,0.58), (6.31,0.26,6.59,0.58), (6.31,0.26,6.59,0.58), (6.31,0.26,6.59,0.58), (6.31,0.26,6.59,0.58), (6.31,0.26,6.59,0.58), (8.89,0.26,9.17,0.58), (8.89,0.26,9.17,0.58), (8.89,0.26,9.17,0.58), (8.89,0.26,9.17,0.58), (12.33,0.26,12.61,0.58), (12.33,0.26,12.61,0.58), (12.33,0.26,12.61,0.58), (12.33,0.26,12.61,0.58), (18.78,0.26,19.06,0.58), (18.78,0.26,19.06,0.58), (20.93,0.26,21.21,0.58), (20.93,0.26,21.21,0.58), (20.93,0.26,21.21,0.58), (20.93,0.26,21.21,0.58), (26.09,0.26,26.37,0.58), (26.09,0.26,26.37,0.58), (8.89,0.42,9.17,1.68), (12.33,0.42,12.61,1.68), (18.78,0.42,19.06,2.1), (20.93,0.42,21.21,1.26), (7.6,0.68,7.88,1), (7.6,0.68,7.88,1), (8.46,0.68,8.74,1), (8.46,0.68,8.74,1), (8.46,0.68,8.74,1), (8.46,0.68,8.74,1), (8.46,0.68,8.74,1), (8.46,0.68,8.74,1), (14.48,0.68,14.76,1), (14.48,0.68,14.76,1), (14.48,0.68,14.76,1), (14.48,0.68,14.76,1), (16.2,0.68,16.48,1), (16.2,0.68,16.48,1), (16.2,0.68,16.48,1), (16.2,0.68,16.48,1), (16.2,0.68,16.48,1), (16.2,0.68,16.48,1), (17.92,0.68,18.2,1), (17.92,0.68,18.2,1), (17.92,0.68,18.2,1), (17.92,0.68,18.2,1), (8.46,0.84,8.74,1.26), (14.48,0.84,14.76,2.52), (16.2,0.84,16.48,1.26), (17.92,0.84,18.2,1.26), (0.72,1.075,1,1.445), (0.72,1.075,1,1.445), (0.72,1.075,1,1.445), (0.72,1.075,1,1.445), (0.72,1.075,1,1.445), (0.72,1.075,1,1.445), (16.2,1.075,16.48,1.445), (16.2,1.075,16.48,1.445), (16.2,1.075,16.48,1.445), (16.2,1.075,16.48,1.445), (16.2,1.075,16.48,1.445), (16.2,1.075,16.48,1.445), (17.92,1.075,18.2,1.445), (17.92,1.075,18.2,1.445), (17.92,1.075,18.2,1.445), (17.92,1.075,18.2,1.445), (20.93,1.075,21.21,1.445), (20.93,1.075,21.21,1.445), (20.93,1.075,21.21,1.445), (20.93,1.075,21.21,1.445), (8.46,1.1,8.74,1.42), (8.46,1.1,8.74,1.42), (8.46,1.1,8.74,1.42), (8.46,1.1,8.74,1.42), (8.46,1.1,8.74,1.42), (8.46,1.1,8.74,1.42), (8.89,1.52,9.17,1.84), (8.89,1.52,9.17,1.84), (8.89,1.52,9.17,1.84), (8.89,1.52,9.17,1.84), (12.33,1.52,12.61,1.84), (12.33,1.52,12.61,1.84), (12.33,1.52,12.61,1.84), (12.33,1.52,12.61,1.84), (14.48,1.94,14.76,2.26), (14.48,1.94,14.76,2.26), (18.78,1.94,19.06,2.26), (18.78,1.94,19.06,2.26), (14.48,2.36,14.76,2.68), (14.48,2.36,14.76,2.68), (14.48,2.36,14.76,2.68), (14.48,2.36,14.76,2.68), (5.45,4.46,5.73,4.78), (5.45,4.46,5.73,4.78), (16.63,4.46,16.91,4.78), (16.63,4.46,16.91,4.78), (20.07,4.46,20.35,4.78), (20.07,4.46,20.35,4.78), (23.51,4.46,23.79,4.78), (23.51,4.46,23.79,4.78), (5.45,4.62,5.73,5.04), (5.45,4.855,5.73,5.225), (5.45,4.855,5.73,5.225), (16.63,4.855,16.91,5.225), (16.63,4.855,16.91,5.225), (20.07,4.855,20.35,5.225), (20.07,4.855,20.35,5.225), (23.51,4.855,23.79,5.225), (23.51,4.855,23.79,5.225), (17.49,6.115,17.77,6.485), (17.49,6.115,17.77,6.485), (17.49,6.115,17.77,6.485), (17.49,6.115,17.77,6.485), (17.49,6.115,17.77,6.485), (17.49,6.115,17.77,6.485), (23.08,6.115,23.36,6.485), (23.08,6.115,23.36,6.485), (23.08,6.115,23.36,6.485), (23.08,6.115,23.36,6.485), (23.08,6.115,23.36,6.485), (23.08,6.115,23.36,6.485), (25.66,6.115,25.94,6.485), (25.66,6.115,25.94,6.485), (25.66,6.115,25.94,6.485), (25.66,6.115,25.94,6.485), (27.38,6.115,27.66,6.485), (27.38,6.115,27.66,6.485), (12.76,6.14,13.04,6.46), (12.76,6.14,13.04,6.46), (17.49,6.3,17.77,6.72), (17.49,6.56,17.77,6.88), (17.49,6.56,17.77,6.88), (17.49,6.56,17.77,6.88), (17.49,6.56,17.77,6.88), (17.49,6.56,17.77,6.88), (17.49,6.56,17.77,6.88)])
P(function_0, met2, [(0,0),(0,0),(0,0),(0,0)],
  [(0,0),(0,0),(0,0),(0,0)],
  [(0,0),(0,0),(0,0),(0,0)],
  [(0,0),(0,0),(0,0),(0,0)],
  [(0,0),(0,0),(0,0),(0,0)])
R(function_0, via2, [(2.91,-0.1,3.11,0.1), (2.91,-0.1,3.11,0.1), (2.91,-0.1,3.11,0.1), (2.91,-0.1,3.11,0.1), (2.91,-0.1,3.11,0.1), (2.91,-0.1,3.11,0.1), (2.91,-0.1,3.11,0.1), (2.91,-0.1,3.11,0.1), (6.35,-0.1,6.55,0.1), (6.35,-0.1,6.55,0.1), (6.35,-0.1,6.55,0.1), (6.35,-0.1,6.55,0.1), (6.35,-0.1,6.55,0.1), (6.35,-0.1,6.55,0.1), (6.35,-0.1,6.55,0.1), (6.35,-0.1,6.55,0.1), (7.64,-0.1,7.84,0.1), (7.64,-0.1,7.84,0.1), (26.13,-0.1,26.33,0.1), (26.13,-0.1,26.33,0.1), (0.76,1.16,0.96,1.36), (0.76,1.16,0.96,1.36), (0.76,1.16,0.96,1.36), (0.76,1.16,0.96,1.36), (0.76,1.16,0.96,1.36), (0.76,1.16,0.96,1.36), (16.24,1.16,16.44,1.36), (16.24,1.16,16.44,1.36), (16.24,1.16,16.44,1.36), (16.24,1.16,16.44,1.36), (16.24,1.16,16.44,1.36), (16.24,1.16,16.44,1.36), (17.96,1.16,18.16,1.36), (17.96,1.16,18.16,1.36), (17.96,1.16,18.16,1.36), (17.96,1.16,18.16,1.36), (20.97,1.16,21.17,1.36), (20.97,1.16,21.17,1.36), (20.97,1.16,21.17,1.36), (20.97,1.16,21.17,1.36), (5.49,4.94,5.69,5.14), (5.49,4.94,5.69,5.14), (16.67,4.94,16.87,5.14), (16.67,4.94,16.87,5.14), (20.11,4.94,20.31,5.14), (20.11,4.94,20.31,5.14), (23.55,4.94,23.75,5.14), (23.55,4.94,23.75,5.14), (17.53,6.2,17.73,6.4), (17.53,6.2,17.73,6.4), (17.53,6.2,17.73,6.4), (17.53,6.2,17.73,6.4), (17.53,6.2,17.73,6.4), (17.53,6.2,17.73,6.4), (23.12,6.2,23.32,6.4), (23.12,6.2,23.32,6.4), (23.12,6.2,23.32,6.4), (23.12,6.2,23.32,6.4), (23.12,6.2,23.32,6.4), (23.12,6.2,23.32,6.4), (25.7,6.2,25.9,6.4), (25.7,6.2,25.9,6.4), (25.7,6.2,25.9,6.4), (25.7,6.2,25.9,6.4), (27.42,6.2,27.62,6.4), (27.42,6.2,27.62,6.4)])
R(function_0, met3, [(2.845,-0.4,3.175,0.4), (2.845,-0.4,3.175,0.4), (2.845,-0.4,3.175,0.4), (2.845,-0.4,3.175,0.4), (2.845,-0.4,3.175,0.4), (2.845,-0.4,3.175,0.4), (2.845,-0.4,3.175,0.4), (2.845,-0.4,3.175,0.4), (3.01,-0.4,6.45,0.4), (6.285,-0.4,6.615,0.4), (6.285,-0.4,6.615,0.4), (6.285,-0.4,6.615,0.4), (6.285,-0.4,6.615,0.4), (6.285,-0.4,6.615,0.4), (6.285,-0.4,6.615,0.4), (6.285,-0.4,6.615,0.4), (6.285,-0.4,6.615,0.4), (7.575,-0.4,7.905,0.4), (7.575,-0.4,7.905,0.4), (7.74,-0.4,26.23,0.4), (26.065,-0.4,26.395,0.4), (26.065,-0.4,26.395,0.4), (0.695,0.86,1.025,1.66), (0.695,0.86,1.025,1.66), (0.695,0.86,1.025,1.66), (0.695,0.86,1.025,1.66), (0.695,0.86,1.025,1.66), (0.695,0.86,1.025,1.66), (0.86,0.86,16.34,1.66), (16.175,0.86,16.505,1.66), (16.175,0.86,16.505,1.66), (16.175,0.86,16.505,1.66), (16.175,0.86,16.505,1.66), (16.175,0.86,16.505,1.66), (16.175,0.86,16.505,1.66), (17.895,0.86,18.225,1.66), (17.895,0.86,18.225,1.66), (17.895,0.86,18.225,1.66), (17.895,0.86,18.225,1.66), (18.06,0.86,21.07,1.66), (20.905,0.86,21.235,1.66), (20.905,0.86,21.235,1.66), (20.905,0.86,21.235,1.66), (20.905,0.86,21.235,1.66), (5.425,4.64,5.755,5.44), (5.425,4.64,5.755,5.44), (5.59,4.64,16.77,5.44), (16.605,4.64,16.935,5.44), (16.605,4.64,16.935,5.44), (20.045,4.64,20.375,5.44), (20.045,4.64,20.375,5.44), (20.21,4.64,23.65,5.44), (23.485,4.64,23.815,5.44), (23.485,4.64,23.815,5.44), (17.465,5.9,17.795,6.7), (17.465,5.9,17.795,6.7), (17.465,5.9,17.795,6.7), (17.465,5.9,17.795,6.7), (17.465,5.9,17.795,6.7), (17.465,5.9,17.795,6.7), (17.63,5.9,23.22,6.7), (23.055,5.9,23.385,6.7), (23.055,5.9,23.385,6.7), (23.055,5.9,23.385,6.7), (23.055,5.9,23.385,6.7), (23.055,5.9,23.385,6.7), (23.055,5.9,23.385,6.7), (23.22,5.9,25.8,6.7), (25.635,5.9,25.965,6.7), (25.635,5.9,25.965,6.7), (25.635,5.9,25.965,6.7), (25.635,5.9,25.965,6.7), (25.8,5.9,27.52,6.7), (27.355,5.9,27.685,6.7), (27.355,5.9,27.685,6.7)])
R(function_0, L104_0, [(-4,-4,33.24,11.56)])
R(function_0, L235_5, [(0,0,29.24,7.56)])
function_0.add(gdstk.Reference(dp_pmos_89584417_x1_y1_1, (10.32,0)))
function_0.add(gdstk.Reference(nmos_s_91441724_x1_y1_16, (24.08,0)))
function_0.add(gdstk.Reference(nmos_s_91441724_x1_y1_16, (29.24,0), rotation=pi, x_reflection=True))
function_0.add(gdstk.Reference(nmos_s_91441724_x1_y1_16, (2.58,0), rotation=pi, x_reflection=True))
function_0.add(gdstk.Reference(nmos_s_91441724_x1_y1_16, (21.5,0)))
function_0.add(gdstk.Reference(nmos_4t_21196599_x1_y1_1, (7.74,0), rotation=pi, x_reflection=True))
function_0.add(gdstk.Reference(nmos_4t_21196599_x1_y1_1, (16.34,0)))
function_0.add(gdstk.Reference(pmos_4t_77116389_x1_y1_1, (7.74,0)))
function_0.add(gdstk.Reference(pmos_4t_77116389_x1_y1_1, (16.34,0), rotation=pi, x_reflection=True))
function_0.add(gdstk.Reference(pmos_4t_77116389_x1_y1_1, (5.16,0), rotation=pi, x_reflection=True))
function_0.add(gdstk.Reference(pmos_4t_77116389_x1_y1_1, (18.92,0)))
function_0.add(gdstk.Label('A', (1.72,4.62), layer=68, texttype=5))
function_0.add(gdstk.Label('B', (22.36,4.62), layer=68, texttype=5))
function_0.add(gdstk.Label('VP', (4.3,6.72), layer=68, texttype=5))
function_0.add(gdstk.Label('D', (19.78,4.62), layer=68, texttype=5))
function_0.add(gdstk.Label('VN', (6.88,6.72), layer=68, texttype=5))
function_0.add(gdstk.Label('F', (28.38,4.62), layer=68, texttype=5))
function_0.add(gdstk.Label('Y', (1.72,0.42), layer=68, texttype=5))
function_0.add(gdstk.Label('E', (6.88,4.62), layer=68, texttype=5))
function_0.add(gdstk.Label('C', (17.2,4.62), layer=68, texttype=5))

lib.write_gds('FUNCTION_0.gds')
